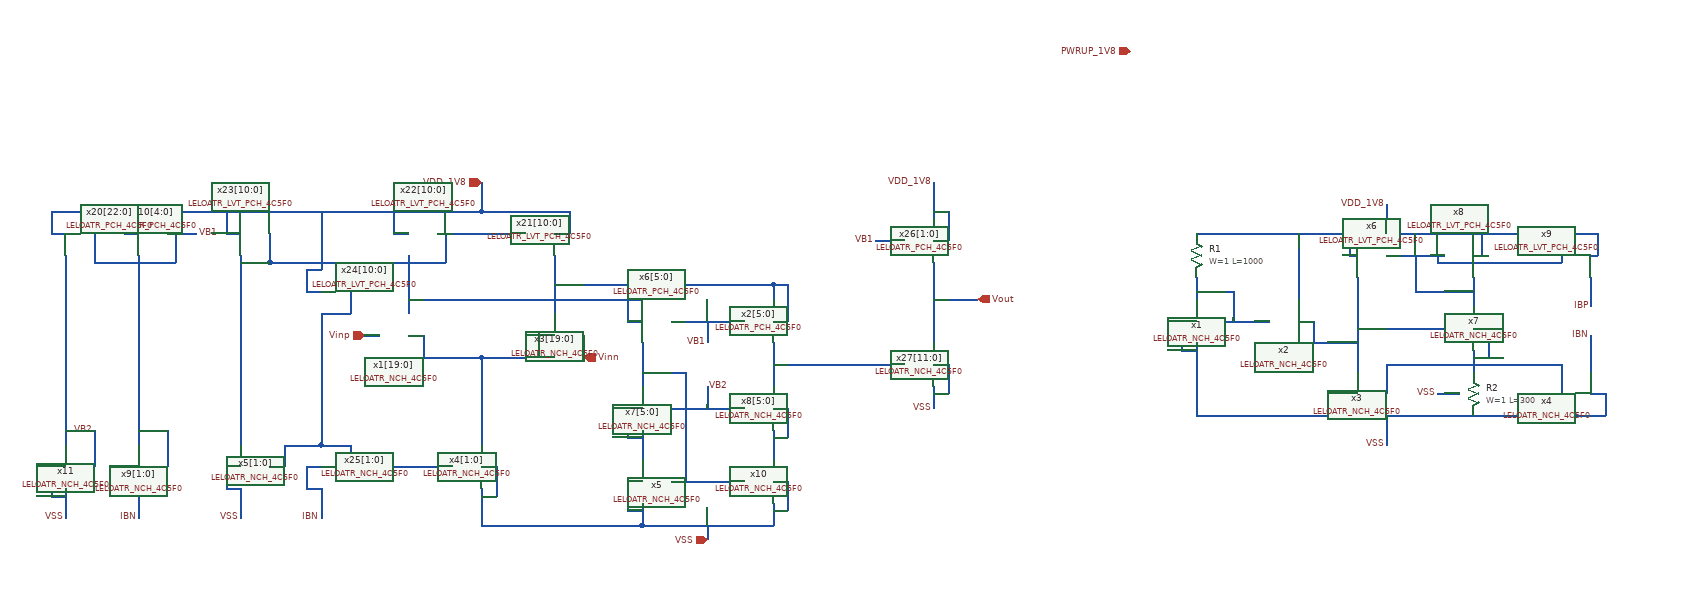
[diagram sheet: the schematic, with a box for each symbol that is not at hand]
v {xschem version=3.4.7 file_version=1.2}
G {}
K {}
V {}
S {}
E {}
P 4 1 -770 140 {}
N 490 40 520 40 {lab=VSS}
N 380 70 540 70 {lab=VSS}
N 540 70 700 70 {lab=VSS}
N 420 70 420 110 {lab=VSS}
N 380 -180 540 -180 {lab=VDD_1V8}
N 540 -180 700 -180 {lab=VDD_1V8}
N 380 -120 380 10 {lab=#net1}
N 420 30 420 40 {lab=#net2}
N 660 30 660 40 {lab=#net2}
N 380 -50 500 -50 {lab=#net1}
N 540 -120 540 -80 {lab=#net3}
N 420 -150 500 -150 {lab=#net3}
N 460 -150 460 -100 {lab=#net3}
N 490 -150 490 -140 {lab=#net3}
N 490 -140 660 -140 {lab=#net3}
N 660 -150 660 -140 {lab=#net3}
N 540 -20 540 10 {lab=#net2}
N 370 -150 380 -150 {lab=VDD_1V8}
N 370 -180 370 -150 {lab=VDD_1V8}
N 540 -150 550 -150 {lab=VDD_1V8}
N 550 -180 550 -150 {lab=VDD_1V8}
N 700 -150 710 -150 {lab=VDD_1V8}
N 710 -180 710 -150 {lab=VDD_1V8}
N 700 -180 710 -180 {lab=VDD_1V8}
N 700 -120 700 -80 {lab=IBP}
N 700 -40 700 10 {lab=IBN}
N 420 -220 420 -180 {lab=VDD_1V8}
N 540 -50 560 -50 {lab=#net2}
N 360 40 380 40 {lab=VSS}
N 360 40 360 70 {lab=VSS}
N 700 40 720 40 {lab=VSS}
N 720 40 720 70 {lab=VSS}
N 700 70 720 70 {lab=VSS}
N 540 -0 660 -0 {lab=#net2}
N 660 -0 660 30 {lab=#net2}
N 420 -0 420 30 {lab=#net2}
N 560 -50 560 -10 {lab=#net2}
N 540 -10 560 -10 {lab=#net2}
N 460 -100 540 -100 {lab=#net3}
N 360 70 380 70 {lab=VSS}
N 420 -0 540 -0 {lab=#net2}
N 370 -180 380 -180 {lab=VDD_1V8}
N 160 -120 160 -90 {lab=#net4}
N 160 -30 160 70 {lab=VSS}
N 300 -30 380 -30 {lab=#net1}
N 200 -60 260 -60 {lab=#net4}
N 210 -100 210 -60 {lab=#net4}
N 160 -100 210 -100 {lab=#net4}
N 160 70 360 70 {lab=VSS}
N 300 -60 320 -60 {lab=#net1}
N 320 -60 320 -30 {lab=#net1}
N 140 -60 160 -60 {lab=VSS}
N 140 -60 140 -20 {lab=VSS}
N 140 -20 160 -20 {lab=VSS}
N 160 -180 370 -180 {lab=VDD_1V8}
N 300 -180 300 -90 {lab=VDD_1V8}
N -820 -10 -720 -10 {lab=#net5}
N -920 -10 -820 -10 {lab=#net5}
N -820 -10 -820 110 {lab=#net5}
N -920 -150 -920 -70 {lab=#net6}
N -880 -180 -760 -180 {lab=#net7}
N -920 -210 -820 -210 {lab=VDD_1V8}
N -820 -250 -820 -210 {lab=VDD_1V8}
N -820 -210 -720 -210 {lab=VDD_1V8}
N -740 -40 -720 -40 {lab=#net5}
N -740 -40 -740 -10 {lab=#net5}
N -920 -40 -900 -40 {lab=#net5}
N -900 -40 -900 -10 {lab=#net5}
N -940 -180 -920 -180 {lab=VDD_1V8}
N -1030 -210 -920 -210 {lab=VDD_1V8}
N -920 -90 -600 -90 {lab=#net6}
N -720 -110 -420 -110 {lab=#net8}
N -420 -110 -420 -90 {lab=#net8}
N -560 -60 -460 -60 {lab=VB1}
N -620 -60 -600 -60 {lab=#net6}
N -620 -90 -620 -60 {lab=#net6}
N -420 -60 -400 -60 {lab=#net8}
N -400 -110 -400 -60 {lab=#net8}
N -420 -110 -400 -110 {lab=#net8}
N -600 -30 -600 30 {lab=#net9}
N -420 -30 -420 30 {lab=#net10}
N -560 60 -460 60 {lab=VB2}
N -600 90 -600 130 {lab=#net11}
N -420 90 -420 130 {lab=#net12}
N -560 160 -460 160 {lab=#net9}
N -420 190 -420 220 {lab=VSS}
N -600 190 -600 220 {lab=VSS}
N -600 220 -420 220 {lab=VSS}
N -510 220 -510 240 {lab=VSS}
N -1150 -150 -1150 -90 {lab=#net7}
N -1110 -180 -1110 -140 {lab=#net7}
N -1110 -140 -950 -140 {lab=#net7}
N -1150 -210 -1030 -210 {lab=VDD_1V8}
N -510 30 -510 60 {lab=VB2}
N -510 -60 -510 -30 {lab=VB1}
N -980 -40 -960 -40 {lab=Vinp}
N -680 -40 -680 -10 {lab=Vinn}
N -1150 -140 -1110 -140 {lab=#net7}
N -1150 170 -1150 210 {lab=VSS}
N -820 170 -820 210 {lab=VSS}
N -820 220 -600 220 {lab=VSS}
N -820 210 -820 220 {lab=VSS}
N -1290 170 -1290 210 {lab=IBN}
N -1290 -150 -1290 110 {lab=VB1}
N -1250 -180 -1210 -180 {lab=VB1}
N -1290 -210 -1150 -210 {lab=VDD_1V8}
N -1310 140 -1290 140 {lab=IBN}
N -1310 140 -1310 170 {lab=IBN}
N -1310 170 -1290 170 {lab=IBN}
N -1310 -180 -1290 -180 {lab=VDD_1V8}
N -1310 -210 -1310 -180 {lab=VDD_1V8}
N -1310 -210 -1290 -210 {lab=VDD_1V8}
N -1240 -180 -1240 -140 {lab=VB1}
N -1290 -140 -1240 -140 {lab=VB1}
N -1170 140 -1150 140 {lab=VSS}
N -1170 140 -1170 170 {lab=VSS}
N -1170 170 -1150 170 {lab=VSS}
N -1170 -180 -1150 -180 {lab=VDD_1V8}
N -1170 -210 -1170 -180 {lab=VDD_1V8}
N -620 60 -600 60 {lab=#net11}
N -620 60 -620 100 {lab=#net11}
N -620 100 -600 100 {lab=#net11}
N -420 60 -400 60 {lab=#net12}
N -400 60 -400 100 {lab=#net12}
N -420 100 -400 100 {lab=#net12}
N -420 160 -400 160 {lab=VSS}
N -400 160 -400 200 {lab=VSS}
N -420 200 -400 200 {lab=VSS}
N -620 160 -600 160 {lab=VSS}
N -620 160 -620 200 {lab=VSS}
N -620 200 -600 200 {lab=VSS}
N -820 140 -800 140 {lab=VSS}
N -800 140 -800 180 {lab=VSS}
N -820 180 -800 180 {lab=VSS}
N -1410 -180 -1390 -180 {lab=VDD_1V8}
N -1410 -210 -1410 -180 {lab=VDD_1V8}
N -1390 -150 -1390 110 {lab=VB2}
N -1350 90 -1350 140 {lab=VB2}
N -1390 90 -1350 90 {lab=VB2}
N -1390 170 -1390 210 {lab=VSS}
N -1410 140 -1390 140 {lab=VSS}
N -1410 140 -1410 180 {lab=VSS}
N -1410 180 -1390 180 {lab=VSS}
N -720 -150 -720 -70 {lab=#net8}
N -720 -180 -700 -180 {lab=VDD_1V8}
N -700 -210 -700 -180 {lab=VDD_1V8}
N -720 -210 -700 -210 {lab=VDD_1V8}
N -920 -150 -920 -70 {lab=#net6}
N -1110 140 -1090 140 {lab=#net13}
N -950 -140 -870 -140 {lab=#net7}
N -870 -180 -870 -140 {lab=#net7}
N -940 -210 -940 -180 {lab=VDD_1V8}
N -1000 -100 -1000 -70 {lab=#net13}
N -1040 -70 -1000 -70 {lab=#net13}
N -1040 -210 -1040 -130 {lab=VDD_1V8}
N -1000 140 -860 140 {lab=#net13}
N -1000 110 -1000 140 {lab=#net13}
N -1040 110 -1000 110 {lab=#net13}
N -1040 -70 -1040 110 {lab=#net13}
N -1040 170 -1040 210 {lab=IBN}
N -1060 140 -1040 140 {lab=IBN}
N -1060 140 -1060 170 {lab=IBN}
N -1060 170 -1040 170 {lab=IBN}
N -1060 -100 -1040 -100 {lab=VDD_1V8}
N -1060 -130 -1060 -100 {lab=VDD_1V8}
N -1060 -130 -1040 -130 {lab=VDD_1V8}
N -1250 90 -1250 140 {lab=VB1}
N -1290 90 -1250 90 {lab=VB1}
N -1350 -140 -1290 -140 {lab=VB1}
N -1350 -180 -1350 -140 {lab=VB1}
N -1090 110 -1040 110 {lab=#net13}
N -1090 110 -1090 140 {lab=#net13}
N -1150 -90 -1150 110 {lab=#net7}
N -540 10 -540 160 {lab=#net9}
N -600 10 -540 10 {lab=#net9}
N -200 -250 -200 -200 {lab=VDD_1V8}
N -200 -170 -180 -170 {lab=VDD_1V8}
N -180 -210 -180 -180 {lab=VDD_1V8}
N -200 -210 -180 -210 {lab=VDD_1V8}
N -180 -180 -180 -170 {lab=VDD_1V8}
N -200 30 -200 60 {lab=VSS}
N -270 0 -240 0 {lab=#net10}
N -200 40 -180 40 {lab=VSS}
N -200 -90 -140 -90 {lab=Vout}
N -200 -140 -200 -30 {lab=Vout}
N -200 0 -180 0 {lab=VSS}
N -180 0 -180 40 {lab=VSS}
N -420 0 -270 0 {lab=#net10}
N -280 -170 -240 -170 {lab=VB1}
N -1410 -210 -1390 -210 {lab=VDD_1V8}
N -1390 -210 -1290 -210 {lab=VDD_1V8}
C {devices/ipin.sym} 70 -430 0 0 {name=p6 lab=PWRUP_1V8}
C {LELO_ATR_SKY130A/LELOATR_NCH_4C5F0.sym} 420 40 0 1 {name=x3 }
C {LELO_ATR_SKY130A/LELOATR_NCH_4C5F0.sym} 660 40 0 0 {name=x4 }
C {LELO_ATR_SKY130A/LELOATR_NCH_4C5F0.sym} 500 -50 0 0 {name=x7}
C {devices/lab_pin.sym} 490 40 0 0 {name=p1 sig_type=std_logic lab=VSS}
C {sky130_fd_pr/res_high_po.sym} 540 40 0 0 {name=R2
W=1
L=300
model=res_high_po
spiceprefix=X
mult=1}
C {devices/lab_pin.sym} 420 110 0 0 {name=p4 sig_type=std_logic lab=VSS}
C {LELO_ATR_SKY130A/LELOATR_LVT_PCH_4C5F0.sym} 500 -150 0 0 {name=x8}
C {LELO_ATR_SKY130A/LELOATR_LVT_PCH_4C5F0.sym} 660 -150 0 0 {name=x9}
C {devices/lab_pin.sym} 420 -220 0 0 {name=p7 sig_type=std_logic lab=VDD_1V8}
C {devices/lab_pin.sym} 700 -80 0 0 {name=p9 sig_type=std_logic lab=IBP}
C {devices/lab_pin.sym} 700 -40 0 0 {name=p10 sig_type=std_logic lab=IBN}
C {LELO_ATR_SKY130A/LELOATR_LVT_PCH_4C5F0.sym} 420 -150 0 1 {name=x6}
C {LELO_ATR_SKY130A/LELOATR_NCH_4C5F0.sym} 200 -60 0 1 {name=x1 }
C {LELO_ATR_SKY130A/LELOATR_NCH_4C5F0.sym} 260 -60 0 0 {name=x2 }
C {sky130_fd_pr/res_high_po.sym} 160 -150 0 0 {name=R1
W=1
L=1000
model=res_high_po
spiceprefix=X
mult=1}
C {devices/opin.sym} -140 -90 0 0 {name=p16 lab=Vout}
C {devices/ipin.sym} -980 -40 0 0 {name=p18 lab=Vinp}
C {devices/ipin.sym} -680 -10 0 1 {name=p19 lab=Vinn}
C {devices/ipin.sym} -510 240 0 0 {name=p20 lab=VSS}
C {devices/ipin.sym} -820 -250 0 0 {name=p21 lab=VDD_1V8}
C {LELO_ATR_SKY130A/LELOATR_NCH_4C5F0.sym} -960 -40 0 0 {name=x1[19:0] }
C {LELO_ATR_SKY130A/LELOATR_NCH_4C5F0.sym} -680 -40 0 1 {name=x3[19:0] }
C {LELO_ATR_SKY130A/LELOATR_PCH_4C5F0.sym} -560 -60 0 1 {name=x6[5:0] }
C {LELO_ATR_SKY130A/LELOATR_PCH_4C5F0.sym} -460 -60 0 0 {name=x2[5:0] }
C {LELO_ATR_SKY130A/LELOATR_NCH_4C5F0.sym} -560 60 0 1 {name=x7[5:0] }
C {LELO_ATR_SKY130A/LELOATR_NCH_4C5F0.sym} -460 60 0 0 {name=x8[5:0] }
C {LELO_ATR_SKY130A/LELOATR_NCH_4C5F0.sym} -560 160 0 1 {name=x5 }
C {LELO_ATR_SKY130A/LELOATR_NCH_4C5F0.sym} -460 160 0 0 {name=x10 }
C {LELO_ATR_SKY130A/LELOATR_NCH_4C5F0.sym} -860 140 0 0 {name=x4[1:0] }
C {devices/lab_pin.sym} -510 -30 0 0 {name=p22 sig_type=std_logic lab=VB1}
C {devices/lab_pin.sym} -510 30 0 1 {name=p23 sig_type=std_logic lab=VB2}
C {LELO_ATR_SKY130A/LELOATR_NCH_4C5F0.sym} -1110 140 0 1 {name=x5[1:0] }
C {LELO_ATR_SKY130A/LELOATR_NCH_4C5F0.sym} -1250 140 0 1 {name=x9[1:0] }
C {LELO_ATR_SKY130A/LELOATR_PCH_4C5F0.sym} -1250 -180 0 1 {name=x10[4:0] }
C {devices/lab_pin.sym} -1210 -180 0 1 {name=p24 sig_type=std_logic lab=VB1}
C {devices/lab_pin.sym} -1350 90 1 0 {name=p25 sig_type=std_logic lab=VB2}
C {LELO_ATR_SKY130A/LELOATR_PCH_4C5F0.sym} -1350 -180 0 1 {name=x20[22:0] }
C {LELO_ATR_SKY130A/LELOATR_NCH_4C5F0.sym} -1350 140 0 1 {name=x11 }
C {devices/lab_pin.sym} -1390 210 0 0 {name=p26 sig_type=std_logic lab=VSS}
C {LELO_ATR_SKY130A/LELOATR_LVT_PCH_4C5F0.sym} -760 -180 0 0 {name=x21[10:0] }
C {LELO_ATR_SKY130A/LELOATR_LVT_PCH_4C5F0.sym} -880 -180 0 1 {name=x22[10:0] }
C {LELO_ATR_SKY130A/LELOATR_LVT_PCH_4C5F0.sym} -1110 -180 0 1 {name=x23[10:0] }
C {LELO_ATR_SKY130A/LELOATR_LVT_PCH_4C5F0.sym} -1000 -100 0 1 {name=x24[10:0] }
C {LELO_ATR_SKY130A/LELOATR_NCH_4C5F0.sym} -1000 140 0 1 {name=x25[1:0] }
C {devices/lab_pin.sym} -1040 210 0 0 {name=p27 sig_type=std_logic lab=IBN}
C {devices/lab_pin.sym} -1290 210 0 0 {name=p28 sig_type=std_logic lab=IBN}
C {devices/lab_pin.sym} -1150 210 0 0 {name=p29 sig_type=std_logic lab=VSS}
C {devices/lab_pin.sym} -200 -250 0 0 {name=p30 sig_type=std_logic lab=VDD_1V8}
C {devices/lab_pin.sym} -200 60 0 0 {name=p31 sig_type=std_logic lab=VSS}
C {LELO_ATR_SKY130A/LELOATR_PCH_4C5F0.sym} -240 -170 0 0 {name=x26[1:0] }
C {LELO_ATR_SKY130A/LELOATR_NCH_4C5F0.sym} -240 0 0 0 {name=x27[11:0] }
C {devices/lab_pin.sym} -280 -170 0 0 {name=p32 sig_type=std_logic lab=VB1}
